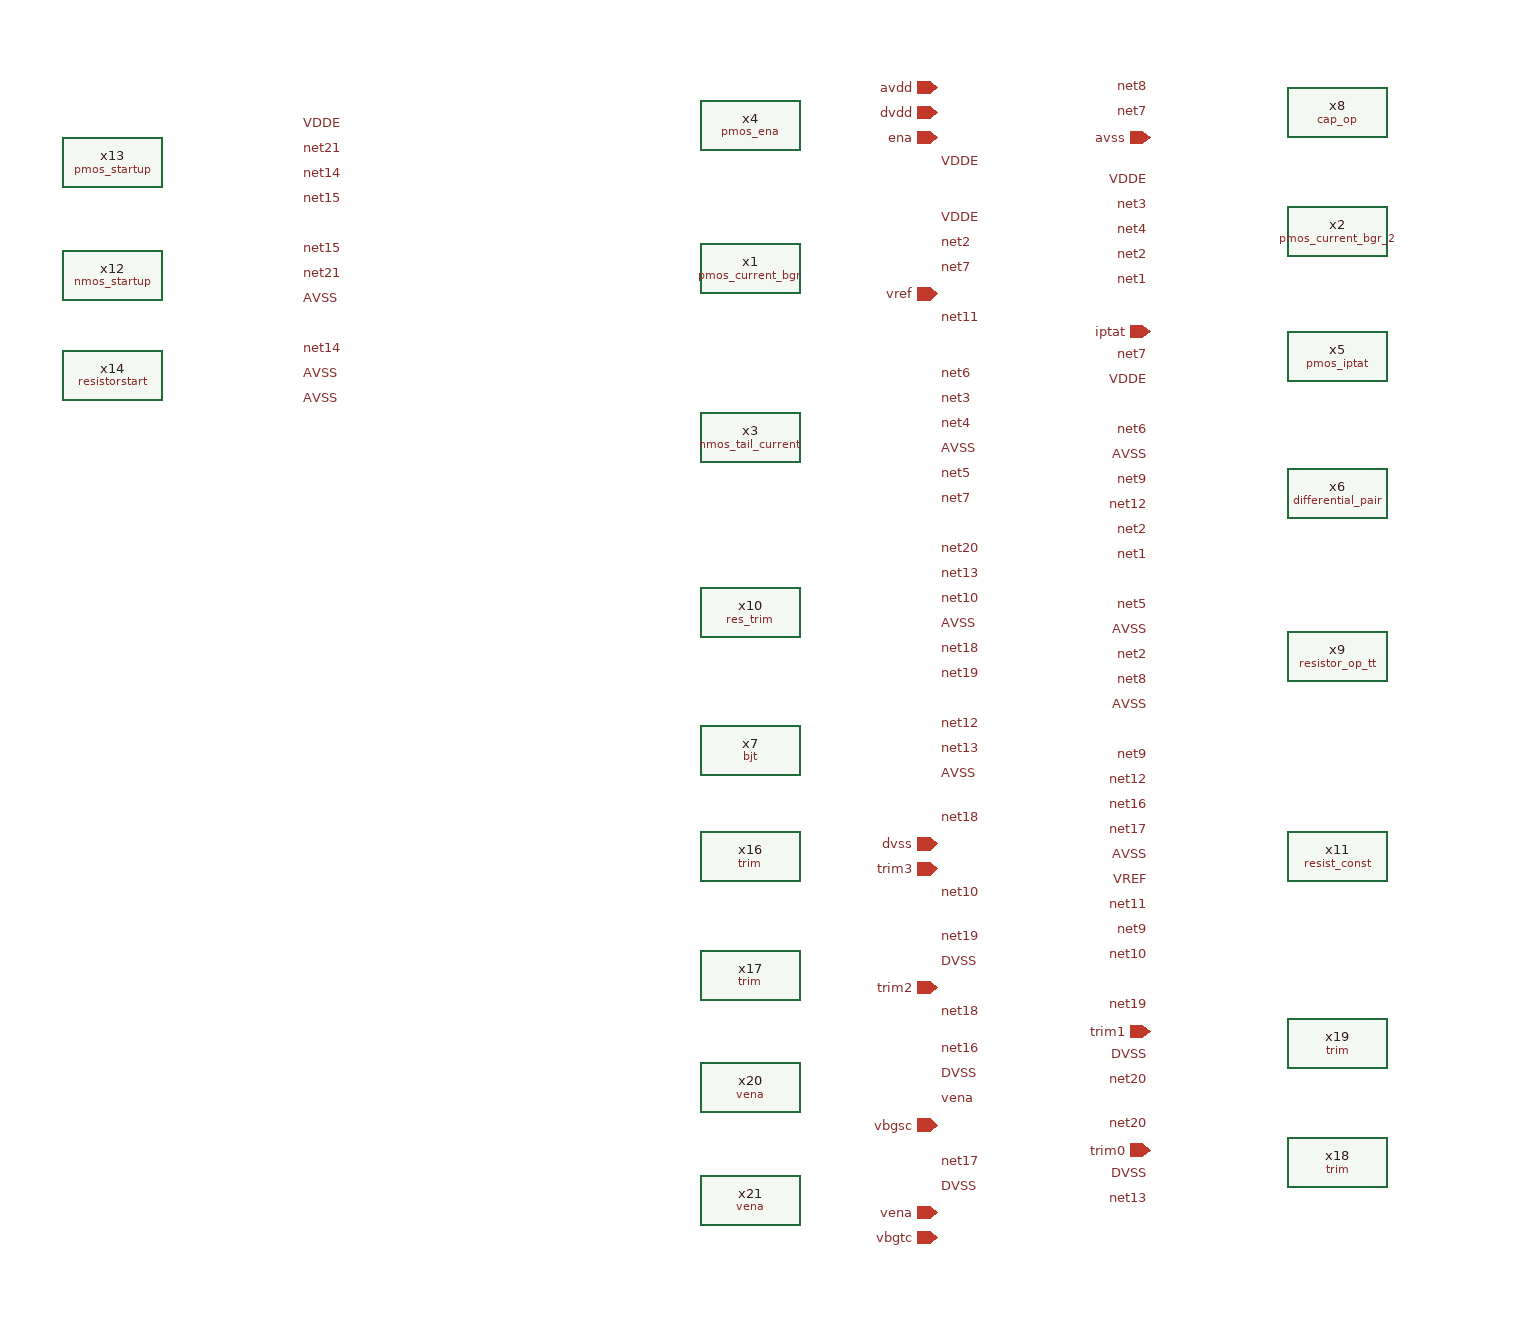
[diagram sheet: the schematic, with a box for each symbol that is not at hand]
v {xschem version=3.4.5 file_version=1.2
}
G {}
K {}
V {}
S {}
E {}
C {/home/gilang_fajrul/chipalooza/sky130_gff_ip__bgr_1.2v/magic/pmos_current_bgr.sym} 860 -1055 0 0 {name=x1}
C {/home/gilang_fajrul/chipalooza/sky130_gff_ip__bgr_1.2v/magic/pmos_current_bgr_2.sym} 1330 -1085 0 1 {name=x2}
C {/home/gilang_fajrul/chipalooza/sky130_gff_ip__bgr_1.2v/magic/nmos_tail_current.sym} 860 -920 0 0 {name=x3}
C {/home/gilang_fajrul/chipalooza/sky130_gff_ip__bgr_1.2v/magic/pmos_ena.sym} 860 -1170 0 0 {name=x4}
C {/home/gilang_fajrul/chipalooza/sky130_gff_ip__bgr_1.2v/magic/pmos_iptat.sym} 1330 -985 2 0 {name=x5}
C {/home/gilang_fajrul/chipalooza/sky130_gff_ip__bgr_1.2v/magic/differential_pair.sym} 1330 -875 2 0 {name=x6}
C {/home/gilang_fajrul/chipalooza/sky130_gff_ip__bgr_1.2v/magic/bjt.sym} 860 -670 0 0 {name=x7}
C {/home/gilang_fajrul/chipalooza/sky130_gff_ip__bgr_1.2v/magic/cap_op.sym} 1330 -1180 2 0 {name=x8}
C {devices/lab_pin.sym} 1180 -1125 0 0 {name=p1 sig_type=std_logic lab=VDDE}
C {devices/lab_pin.sym} 1010 -1140 2 0 {name=p2 sig_type=std_logic lab=VDDE}
C {devices/lab_pin.sym} 1180 -965 0 0 {name=p3 sig_type=std_logic lab=VDDE}
C {devices/lab_pin.sym} 1010 -1095 2 0 {name=p4 sig_type=std_logic lab=VDDE}
C {/home/gilang_fajrul/chipalooza/sky130_gff_ip__bgr_1.2v/magic/resistor_op_tt.sym} 1330 -745 2 0 {name=x9}
C {devices/lab_pin.sym} 1180 -1045 0 0 {name=p5 sig_type=std_logic lab=net1}
C {devices/lab_pin.sym} 1180 -825 0 0 {name=p6 sig_type=std_logic lab=net1}
C {devices/lab_pin.sym} 1180 -845 0 0 {name=p7 sig_type=std_logic lab=net2}
C {devices/lab_pin.sym} 1180 -1065 0 0 {name=p8 sig_type=std_logic lab=net2}
C {devices/lab_pin.sym} 1180 -1105 0 0 {name=p9 sig_type=std_logic lab=net3}
C {devices/lab_pin.sym} 1010 -950 2 0 {name=p10 sig_type=std_logic lab=net3}
C {devices/lab_pin.sym} 1180 -1085 0 0 {name=p11 sig_type=std_logic lab=net4}
C {devices/lab_pin.sym} 1010 -930 2 0 {name=p12 sig_type=std_logic lab=net4}
C {devices/lab_pin.sym} 1010 -910 2 0 {name=p13 sig_type=std_logic lab=AVSS}
C {devices/lab_pin.sym} 1180 -705 0 0 {name=p14 sig_type=std_logic lab=AVSS}
C {devices/lab_pin.sym} 1010 -890 2 0 {name=p16 sig_type=std_logic lab=net5}
C {devices/lab_pin.sym} 1180 -785 0 0 {name=p17 sig_type=std_logic lab=net5}
C {devices/lab_pin.sym} 1010 -970 2 0 {name=p18 sig_type=std_logic lab=net6}
C {devices/lab_pin.sym} 1180 -925 0 0 {name=p19 sig_type=std_logic lab=net6}
C {devices/lab_pin.sym} 1010 -870 2 0 {name=p20 sig_type=std_logic lab=net7}
C {devices/lab_pin.sym} 1010 -650 2 0 {name=p22 sig_type=std_logic lab=AVSS}
C {devices/lab_pin.sym} 1180 -905 0 0 {name=p23 sig_type=std_logic lab=AVSS}
C {devices/lab_pin.sym} 1180 -765 0 0 {name=p26 sig_type=std_logic lab=AVSS}
C {devices/lab_pin.sym} 1180 -745 0 0 {name=p27 sig_type=std_logic lab=net2}
C {devices/lab_pin.sym} 1010 -1075 2 0 {name=p24 sig_type=std_logic lab=net2}
C {devices/lab_pin.sym} 1180 -725 0 0 {name=p25 sig_type=std_logic lab=net8}
C {devices/lab_pin.sym} 1180 -1200 0 0 {name=p28 sig_type=std_logic lab=net8}
C {devices/lab_pin.sym} 1180 -1180 0 0 {name=p29 sig_type=std_logic lab=net7}
C {devices/lab_pin.sym} 1010 -1055 2 0 {name=p30 sig_type=std_logic lab=net7}
C {devices/lab_pin.sym} 1180 -985 0 0 {name=p31 sig_type=std_logic lab=net7}
C {/home/gilang_fajrul/chipalooza/sky130_gff_ip__bgr_1.2v/magic/res_trim.sym} 860 -780 0 0 {name=x10}
C {devices/lab_pin.sym} 1010 -770 2 0 {name=p35 sig_type=std_logic lab=AVSS}
C {/home/gilang_fajrul/chipalooza/sky130_gff_ip__bgr_1.2v/magic/resist_const.sym} 1330 -585 2 0 {name=x11}
C {devices/lab_pin.sym} 1180 -585 0 0 {name=p36 sig_type=std_logic lab=AVSS}
C {devices/lab_pin.sym} 1180 -565 0 0 {name=p38 sig_type=std_logic lab=VREF}
C {devices/lab_pin.sym} 1180 -625 0 0 {name=p39 sig_type=std_logic lab=net16}
C {devices/lab_pin.sym} 1180 -605 0 0 {name=p40 sig_type=std_logic lab=net17}
C {devices/lab_pin.sym} 1180 -665 0 0 {name=p41 sig_type=std_logic lab=net9}
C {devices/lab_pin.sym} 1180 -525 0 0 {name=p42 sig_type=std_logic lab=net9}
C {devices/lab_pin.sym} 1180 -505 0 0 {name=p43 sig_type=std_logic lab=net10}
C {devices/lab_pin.sym} 1010 -790 2 0 {name=p44 sig_type=std_logic lab=net10}
C {devices/lab_pin.sym} 1010 -1015 2 0 {name=p45 sig_type=std_logic lab=net11}
C {devices/lab_pin.sym} 1180 -545 0 0 {name=p46 sig_type=std_logic lab=net11}
C {devices/lab_pin.sym} 1180 -645 0 0 {name=p47 sig_type=std_logic lab=net12}
C {devices/lab_pin.sym} 1010 -690 2 0 {name=p48 sig_type=std_logic lab=net12}
C {devices/lab_pin.sym} 1010 -670 2 0 {name=p49 sig_type=std_logic lab=net13}
C {devices/lab_pin.sym} 1010 -810 2 0 {name=p50 sig_type=std_logic lab=net13}
C {devices/lab_pin.sym} 1180 -885 0 0 {name=p51 sig_type=std_logic lab=net9}
C {devices/lab_pin.sym} 1180 -865 0 0 {name=p52 sig_type=std_logic lab=net12}
C {/home/gilang_fajrul/chipalooza/sky130_gff_ip__bgr_1.2v/magic/nmos_startup.sym} 350 -1050 0 0 {name=x12}
C {/home/gilang_fajrul/chipalooza/sky130_gff_ip__bgr_1.2v/magic/pmos_startup.sym} 350 -1140 0 0 {name=x13}
C {/home/gilang_fajrul/chipalooza/sky130_gff_ip__bgr_1.2v/magic/resistorstart.sym} 350 -970 0 0 {name=x14}
C {devices/lab_pin.sym} 500 -1130 2 0 {name=p54 sig_type=std_logic lab=net14}
C {devices/lab_pin.sym} 500 -1150 2 0 {name=p55 sig_type=std_logic lab=net21}
C {devices/lab_pin.sym} 500 -990 2 0 {name=p56 sig_type=std_logic lab=net14}
C {devices/lab_pin.sym} 500 -950 2 0 {name=p57 sig_type=std_logic lab=AVSS}
C {devices/lab_pin.sym} 500 -1030 2 0 {name=p58 sig_type=std_logic lab=AVSS}
C {devices/lab_pin.sym} 500 -970 2 0 {name=p59 sig_type=std_logic lab=AVSS}
C {devices/lab_pin.sym} 500 -1170 2 0 {name=p60 sig_type=std_logic lab=VDDE}
C {devices/lab_pin.sym} 500 -1110 2 0 {name=p61 sig_type=std_logic lab=net15}
C {devices/lab_pin.sym} 500 -1070 2 0 {name=p62 sig_type=std_logic lab=net15}
C {devices/lab_pin.sym} 500 -1050 2 0 {name=p63 sig_type=std_logic lab=net21}
C {devices/lab_pin.sym} 1010 -750 2 0 {name=p75 sig_type=std_logic lab=net18}
C {devices/lab_pin.sym} 1010 -730 2 0 {name=p76 sig_type=std_logic lab=net19}
C {devices/lab_pin.sym} 1010 -830 2 0 {name=p77 sig_type=std_logic lab=net20}
C {/home/gilang_fajrul/chipalooza/sky130_gff_ip__bgr_1.2v/magic/trim.sym} 860 -585 0 0 {name=x16}
C {/home/gilang_fajrul/chipalooza/sky130_gff_ip__bgr_1.2v/magic/trim.sym} 860 -490 0 0 {name=x17}
C {/home/gilang_fajrul/chipalooza/sky130_gff_ip__bgr_1.2v/magic/trim.sym} 1330 -340 2 0 {name=x18}
C {/home/gilang_fajrul/chipalooza/sky130_gff_ip__bgr_1.2v/magic/trim.sym} 1330 -435 2 0 {name=x19}
C {devices/lab_pin.sym} 1010 -500 2 0 {name=p69 sig_type=std_logic lab=DVSS}
C {devices/lab_pin.sym} 1180 -330 0 0 {name=p70 sig_type=std_logic lab=DVSS}
C {devices/lab_pin.sym} 1180 -425 0 0 {name=p71 sig_type=std_logic lab=DVSS}
C {devices/lab_pin.sym} 1010 -555 2 0 {name=p79 sig_type=std_logic lab=net10}
C {devices/lab_pin.sym} 1010 -615 2 0 {name=p80 sig_type=std_logic lab=net18}
C {devices/lab_pin.sym} 1010 -460 2 0 {name=p81 sig_type=std_logic lab=net18}
C {devices/lab_pin.sym} 1010 -520 2 0 {name=p82 sig_type=std_logic lab=net19}
C {devices/lab_pin.sym} 1180 -465 0 0 {name=p83 sig_type=std_logic lab=net19}
C {devices/lab_pin.sym} 1180 -405 0 0 {name=p84 sig_type=std_logic lab=net20}
C {devices/lab_pin.sym} 1180 -370 0 0 {name=p85 sig_type=std_logic lab=net20}
C {devices/lab_pin.sym} 1180 -310 0 0 {name=p86 sig_type=std_logic lab=net13}
C {/home/gilang_fajrul/chipalooza/sky130_gff_ip__bgr_1.2v/magic/vena.sym} 860 -400 0 0 {name=x20}
C {/home/gilang_fajrul/chipalooza/sky130_gff_ip__bgr_1.2v/magic/vena.sym} 860 -310 0 0 {name=x21}
C {devices/lab_pin.sym} 1010 -430 2 0 {name=p21 sig_type=std_logic lab=net16}
C {devices/lab_pin.sym} 1010 -340 2 0 {name=p87 sig_type=std_logic lab=net17}
C {devices/lab_pin.sym} 1010 -410 2 0 {name=p88 sig_type=std_logic lab=DVSS}
C {devices/lab_pin.sym} 1010 -320 2 0 {name=p89 sig_type=std_logic lab=DVSS}
C {devices/lab_pin.sym} 1010 -390 2 0 {name=p90 sig_type=std_logic lab=vena}
C {devices/iopin.sym} 1010 -1200 0 0 {name=p32 lab=avdd}
C {devices/iopin.sym} 1010 -1180 0 0 {name=p33 lab=dvdd}
C {devices/iopin.sym} 1010 -1160 0 0 {name=p34 lab=ena}
C {devices/iopin.sym} 1010 -1035 0 0 {name=p37 lab=vref}
C {devices/iopin.sym} 1010 -370 0 0 {name=p64 lab=vbgsc}
C {devices/iopin.sym} 1010 -280 0 0 {name=p65 lab=vbgtc}
C {devices/iopin.sym} 1010 -300 0 0 {name=p66 lab=vena}
C {devices/iopin.sym} 1180 -1160 2 0 {name=p15 lab=avss}
C {devices/iopin.sym} 1010 -595 0 0 {name=p67 lab=dvss}
C {devices/iopin.sym} 1180 -350 2 0 {name=p68 lab=trim0}
C {devices/iopin.sym} 1180 -445 2 0 {name=p74 lab=trim1}
C {devices/iopin.sym} 1010 -480 0 0 {name=p73 lab=trim2}
C {devices/iopin.sym} 1010 -575 0 0 {name=p72 lab=trim3}
C {devices/iopin.sym} 1180 -1005 2 0 {name=p53 lab=iptat}
